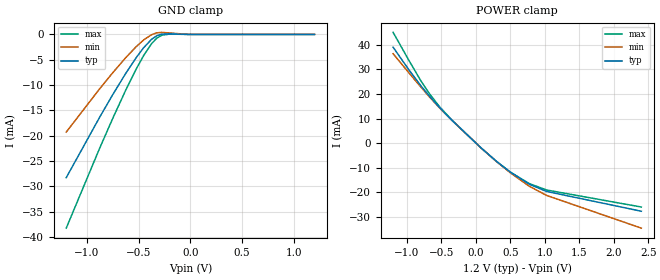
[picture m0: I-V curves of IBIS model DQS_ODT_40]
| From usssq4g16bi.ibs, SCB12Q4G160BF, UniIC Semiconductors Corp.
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|   Model DQS_ODT_40
[Model] DQS_ODT_40
Model_type Input
Polarity   Non-Inverting
Enable   Active-High
Vinl =  8.300E-01
Vinh =  9.700E-01
C_comp   7.827E-13   7.748E-13   8.022E-13
C_comp_power_clamp   2.050E-13   1.847E-13   2.346E-13
C_comp_gnd_clamp   5.777E-13   5.676E-13   5.901E-13
[Model Spec]
Vinh   9.700E-01   9.250E-01   1.015E+00
Vinl   8.300E-01   7.850E-01   8.750E-01
[Temperature Range]   45.000   95.000   -40.000
[Voltage Range]   1.200E+00   1.140E+00   1.260E+00
[C Comp Corner]
C_comp_power_clamp   2.050E-13   1.847E-13   2.346E-13
C_comp_gnd_clamp   5.777E-13   5.901E-13   5.676E-13
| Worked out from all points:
|   GND clamp passes 1 mA (typ) near -0.38 V on its own axis
|   POWER clamp passes 1 mA (typ) near -0.04 V on its own axis
[GND_clamp]
|Voltage   I(typ)   I(min)   I(max)
-1.2V     -28.31mA   -19.3mA    -38.28mA
-875mV    -16.3mA    -10.7mA    -22.4mA
-750mV    -11.89mA   -7.566mA   -16.58mA
-625mV    -7.714mA   -4.602mA   -11.03mA
-525mV    -4.633mA   -2.451mA   -6.902mA
-450mV    -2.592mA   -1.071mA   -4.123mA
-375mV    -973.6uA   -56.79uA   -1.832mA
-325mV    -274uA     305uA      -753.5uA
-275mV    59.15uA    401.4uA    -154.4uA
-200mV    121.1uA    281.3uA    62.53uA
-25mV     0A         0A         0A
1.2V      0A         0A         0A
[POWER_clamp]
|Voltage   I(typ)   I(min)   I(max)
-1.2V     39.02mA    36.37mA    45.05mA
-975mV    29.96mA    28.73mA    33.85mA
-800mV    23.42mA    22.89mA    25.47mA
-675mV    19.16mA    18.84mA    20.17mA
-525mV    14.42mA    14.27mA    14.78mA
-350mV    9.362mA    9.33mA     9.476mA
75mV      -1.94mA    -1.938mA   -1.965mA
300mV     -7.432mA   -7.509mA   -7.479mA
500mV     -11.81mA   -12.08mA   -11.79mA
775mV     -16.73mA   -17.55mA   -16.47mA
1.025V    -19.66mA   -21.27mA   -19.07mA
2.4V      -27.71mA   -34.59mA   -26mA
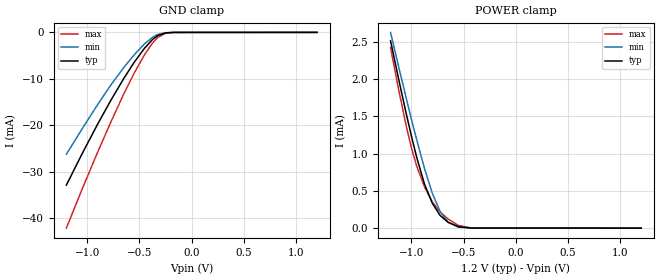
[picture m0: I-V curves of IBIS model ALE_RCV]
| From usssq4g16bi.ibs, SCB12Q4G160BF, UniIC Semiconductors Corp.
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|   Model ALE_RCV
[Model] ALE_RCV
Model_type Input
Polarity   Non-Inverting
Enable   Active-High
Vinl =  2.400E-01
Vinh =  9.600E-01
C_comp   7.066E-13   6.972E-13   7.169E-13
C_comp_power_clamp   9.626E-14   3.705E-14   1.111E-13
C_comp_gnd_clamp   6.104E-13   6.058E-13   6.601E-13
[Model Spec]
Vinh   9.600E-01   9.120E-01   1.008E+00
Vinl   2.400E-01   2.280E-01   2.520E-01
[Temperature Range]   45.000   95.000   -40.000
[Voltage Range]   1.200E+00   1.140E+00   1.260E+00
[C Comp Corner]
C_comp_power_clamp   9.626E-14   1.111E-13   3.705E-14
C_comp_gnd_clamp   6.104E-13   6.058E-13   6.601E-13
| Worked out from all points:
|   GND clamp passes 1 mA (typ) near -0.35 V on its own axis
|   POWER clamp passes 1 mA (typ) near -0.96 V on its own axis
[GND_clamp]
|Voltage   I(typ)   I(min)   I(max)
-1.2V     -32.89mA   -26.25mA   -42.15mA
-1.05V    -26.17mA   -20.81mA   -33.8mA
-900mV    -19.74mA   -15.53mA   -25.78mA
-775mV    -14.67mA   -11.37mA   -19.35mA
-650mV    -9.913mA   -7.565mA   -13.25mA
-550mV    -6.428mA   -4.817mA   -8.75mA
-450mV    -3.367mA   -2.432mA   -4.753mA
-375mV    -1.535mA   -1.055mA   -2.293mA
-325mV    -689.4uA   -458.9uA   -1.089mA
-250mV    -113.6uA   -79.32uA   -186uA
-175mV    -10.33uA   -8.935uA   -14.22uA
1.2V      0A         0A         0A
[POWER_clamp]
|Voltage   I(typ)   I(min)   I(max)
-1.2V     2.514mA    2.628mA    2.425mA
-1.125V   2.017mA    2.182mA    1.878mA
-1.05V    1.538mA    1.746mA    1.372mA
-1V       1.235mA    1.463mA    1.077mA
-950mV    952.5uA    1.189mA    833.5uA
-875mV    591.3uA    802uA      554.9uA
-800mV    333.7uA    467uA      351.1uA
-725mV    169.9uA    220.7uA    219uA
-650mV    79.46uA    80.36uA    123.7uA
-550mV    18.75uA    13.3uA     35.96uA
-425mV    915.2nA    774.2nA    1.575uA
1.2V      0A         0A         9.82nA
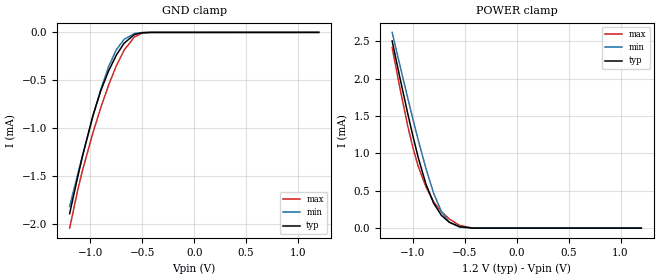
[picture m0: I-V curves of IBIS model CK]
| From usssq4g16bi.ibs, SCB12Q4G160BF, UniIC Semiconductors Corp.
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|   Model CK
[Model] CK
Model_type Input
Polarity   Non-Inverting
Enable   Active-High
Vinl =  5.100E-01
Vinh =  6.900E-01
C_comp   3.840E-13   3.780E-13   3.895E-13
C_comp_power_clamp   4.721E-14   4.416E-14   5.044E-14
C_comp_gnd_clamp   1.448E-13   1.443E-13   1.449E-13
[Model Spec]
Vinh   6.900E-01   6.600E-01   7.200E-01
Vinl   5.100E-01   4.800E-01   5.400E-01
[Temperature Range]   45.000   95.000   -40.000
[Voltage Range]   1.200E+00   1.140E+00   1.260E+00
[C Comp Corner]
C_comp_power_clamp   4.721E-14   5.044E-14   4.416E-14
C_comp_gnd_clamp   1.448E-13   1.443E-13   1.449E-13
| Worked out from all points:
|   GND clamp passes 1 mA (typ) near -1.01 V on its own axis
|   POWER clamp passes 1 mA (typ) near -0.96 V on its own axis
[GND_clamp]
|Voltage   I(typ)   I(min)   I(max)
-1.2V     -1.894mA   -1.819mA   -2.046mA
-1.125V   -1.523mA   -1.494mA   -1.661mA
-1.075V   -1.288mA   -1.281mA   -1.437mA
-975mV    -866.6uA   -874.5uA   -1.046mA
-900mV    -609.5uA   -595.9uA   -786.5uA
-825mV    -402.8uA   -357.8uA   -551.8uA
-750mV    -236.9uA   -181.2uA   -348.1uA
-675mV    -112.4uA   -72.29uA   -184.6uA
-575mV    -22.31uA   -11.6uA    -46.86uA
-500mV    -3.511uA   -1.889uA   -8.391uA
-425mV    -375.9nA   -250.4nA   -804.5nA
1.2V      0A         0A         0A
[POWER_clamp]
|Voltage   I(typ)   I(min)   I(max)
-1.2V     2.507mA    2.622mA    2.418mA
-1.125V   2.012mA    2.178mA    1.873mA
-1.05V    1.535mA    1.743mA    1.369mA
-1V       1.233mA    1.46mA     1.076mA
-950mV    950.8uA    1.187mA    832.9uA
-875mV    590.7uA    800.8uA    555uA
-800mV    333.6uA    466.4uA    351.2uA
-725mV    169.9uA    220.5uA    219.1uA
-650mV    79.46uA    80.27uA    123.9uA
-550mV    18.76uA    13.22uA    36.16uA
-425mV    907.7nA    698.5nA    1.713uA
1.2V      0A         0A         0A
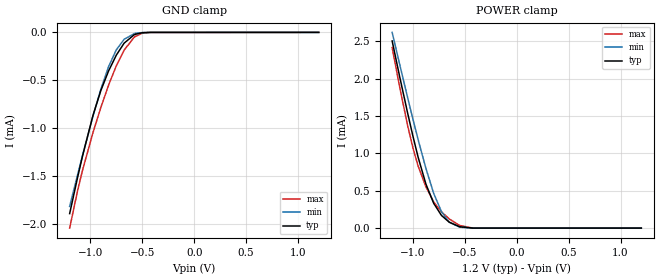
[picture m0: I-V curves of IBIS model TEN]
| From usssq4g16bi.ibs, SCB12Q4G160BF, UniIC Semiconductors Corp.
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|   Model TEN
[Model] TEN
Model_type Input
Polarity   Non-Inverting
Enable   Active-High
Vinl =  2.400E-01
Vinh =  9.600E-01
C_comp   3.775E-13   3.769E-13   3.784E-13
C_comp_power_clamp   1.278E-13   1.110E-13   1.533E-13
C_comp_gnd_clamp   2.491E-13   2.242E-13   2.674E-13
[Model Spec]
Vinh   9.600E-01   9.120E-01   1.008E+00
Vinl   2.400E-01   2.280E-01   2.520E-01
[Temperature Range]   45.000   95.000   -40.000
[Voltage Range]   1.200E+00   1.140E+00   1.260E+00
[C Comp Corner]
C_comp_power_clamp   1.278E-13   1.110E-13   1.533E-13
C_comp_gnd_clamp   2.491E-13   2.674E-13   2.242E-13
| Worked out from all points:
|   GND clamp passes 1 mA (typ) near -1.01 V on its own axis
|   POWER clamp passes 1 mA (typ) near -0.96 V on its own axis
[GND_clamp]
|Voltage   I(typ)   I(min)   I(max)
-1.2V     -1.894mA   -1.819mA   -2.046mA
-1.125V   -1.523mA   -1.494mA   -1.661mA
-1.075V   -1.288mA   -1.281mA   -1.437mA
-975mV    -866.6uA   -874.5uA   -1.046mA
-900mV    -609.5uA   -595.9uA   -786.5uA
-825mV    -402.8uA   -357.8uA   -551.8uA
-750mV    -236.9uA   -181.2uA   -348.1uA
-675mV    -112.4uA   -72.29uA   -184.6uA
-575mV    -22.31uA   -11.6uA    -46.86uA
-500mV    -3.511uA   -1.89uA    -8.391uA
-425mV    -376nA     -250.4nA   -804.7nA
1.2V      0A         -7.621pA   0A
[POWER_clamp]
|Voltage   I(typ)   I(min)   I(max)
-1.2V     2.507mA    2.622mA    2.418mA
-1.125V   2.012mA    2.178mA    1.872mA
-1.05V    1.535mA    1.743mA    1.368mA
-1V       1.233mA    1.46mA     1.075mA
-950mV    950.7uA    1.187mA    832.4uA
-875mV    590.6uA    800.7uA    554.4uA
-800mV    333.4uA    466.4uA    350.8uA
-725mV    169.8uA    220.5uA    218.7uA
-650mV    79.35uA    80.24uA    123.5uA
-550mV    18.67uA    13.19uA    35.89uA
-425mV    849.7nA    680.9nA    1.522uA
1.2V      0A         0A         0A
